VERSION 5.7 ;
BUSBITCHARS "[]" ;
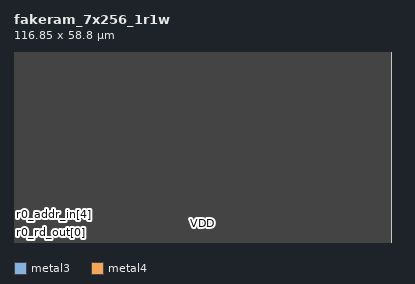
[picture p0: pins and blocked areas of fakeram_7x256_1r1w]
MACRO fakeram_7x256_1r1w
  FOREIGN fakeram_7x256_1r1w 0 0 ;
  SYMMETRY X Y R90 ;
  SIZE 116.850 BY 58.800 ;
  CLASS BLOCK ;
  PIN w0_wd_in[0]
    DIRECTION INPUT ;
    USE SIGNAL ;
    SHAPE ABUTMENT ;
    PORT
      LAYER metal3 ;
      RECT 0.000 0.280 0.140 0.420 ;
    END
  END w0_wd_in[0]
  PIN w0_wd_in[1]
    DIRECTION INPUT ;
    USE SIGNAL ;
    SHAPE ABUTMENT ;
    PORT
      LAYER metal3 ;
      RECT 0.000 0.560 0.140 0.700 ;
    END
  END w0_wd_in[1]
  PIN w0_wd_in[2]
    DIRECTION INPUT ;
    USE SIGNAL ;
    SHAPE ABUTMENT ;
    PORT
      LAYER metal3 ;
      RECT 0.000 0.840 0.140 0.980 ;
    END
  END w0_wd_in[2]
  PIN w0_wd_in[3]
    DIRECTION INPUT ;
    USE SIGNAL ;
    SHAPE ABUTMENT ;
    PORT
      LAYER metal3 ;
      RECT 0.000 1.120 0.140 1.260 ;
    END
  END w0_wd_in[3]
  PIN w0_wd_in[4]
    DIRECTION INPUT ;
    USE SIGNAL ;
    SHAPE ABUTMENT ;
    PORT
      LAYER metal3 ;
      RECT 0.000 1.400 0.140 1.540 ;
    END
  END w0_wd_in[4]
  PIN w0_wd_in[5]
    DIRECTION INPUT ;
    USE SIGNAL ;
    SHAPE ABUTMENT ;
    PORT
      LAYER metal3 ;
      RECT 0.000 1.680 0.140 1.820 ;
    END
  END w0_wd_in[5]
  PIN w0_wd_in[6]
    DIRECTION INPUT ;
    USE SIGNAL ;
    SHAPE ABUTMENT ;
    PORT
      LAYER metal3 ;
      RECT 0.000 1.960 0.140 2.100 ;
    END
  END w0_wd_in[6]
  PIN w0_addr_in[0]
    DIRECTION INPUT ;
    USE SIGNAL ;
    SHAPE ABUTMENT ;
    PORT
      LAYER metal3 ;
      RECT 0.000 2.240 0.140 2.380 ;
    END
  END w0_addr_in[0]
  PIN w0_addr_in[1]
    DIRECTION INPUT ;
    USE SIGNAL ;
    SHAPE ABUTMENT ;
    PORT
      LAYER metal3 ;
      RECT 0.000 2.520 0.140 2.660 ;
    END
  END w0_addr_in[1]
  PIN w0_addr_in[2]
    DIRECTION INPUT ;
    USE SIGNAL ;
    SHAPE ABUTMENT ;
    PORT
      LAYER metal3 ;
      RECT 0.000 2.800 0.140 2.940 ;
    END
  END w0_addr_in[2]
  PIN w0_addr_in[3]
    DIRECTION INPUT ;
    USE SIGNAL ;
    SHAPE ABUTMENT ;
    PORT
      LAYER metal3 ;
      RECT 0.000 3.080 0.140 3.220 ;
    END
  END w0_addr_in[3]
  PIN w0_addr_in[4]
    DIRECTION INPUT ;
    USE SIGNAL ;
    SHAPE ABUTMENT ;
    PORT
      LAYER metal3 ;
      RECT 0.000 3.360 0.140 3.500 ;
    END
  END w0_addr_in[4]
  PIN w0_addr_in[5]
    DIRECTION INPUT ;
    USE SIGNAL ;
    SHAPE ABUTMENT ;
    PORT
      LAYER metal3 ;
      RECT 0.000 3.640 0.140 3.780 ;
    END
  END w0_addr_in[5]
  PIN w0_addr_in[6]
    DIRECTION INPUT ;
    USE SIGNAL ;
    SHAPE ABUTMENT ;
    PORT
      LAYER metal3 ;
      RECT 0.000 3.920 0.140 4.060 ;
    END
  END w0_addr_in[6]
  PIN w0_addr_in[7]
    DIRECTION INPUT ;
    USE SIGNAL ;
    SHAPE ABUTMENT ;
    PORT
      LAYER metal3 ;
      RECT 0.000 4.200 0.140 4.340 ;
    END
  END w0_addr_in[7]
  PIN w0_clk
    DIRECTION INPUT ;
    USE SIGNAL ;
    SHAPE ABUTMENT ;
    PORT
      LAYER metal3 ;
      RECT 0.000 4.480 0.140 4.620 ;
    END
  END w0_clk
  PIN w0_ce_in
    DIRECTION INPUT ;
    USE SIGNAL ;
    SHAPE ABUTMENT ;
    PORT
      LAYER metal3 ;
      RECT 0.000 4.760 0.140 4.900 ;
    END
  END w0_ce_in
  PIN w0_we_in
    DIRECTION INPUT ;
    USE SIGNAL ;
    SHAPE ABUTMENT ;
    PORT
      LAYER metal3 ;
      RECT 0.000 5.040 0.140 5.180 ;
    END
  END w0_we_in
  PIN r0_rd_out[0]
    DIRECTION OUTPUT ;
    USE SIGNAL ;
    SHAPE ABUTMENT ;
    PORT
      LAYER metal3 ;
      RECT 0.000 5.320 0.140 5.460 ;
    END
  END r0_rd_out[0]
  PIN r0_rd_out[1]
    DIRECTION OUTPUT ;
    USE SIGNAL ;
    SHAPE ABUTMENT ;
    PORT
      LAYER metal3 ;
      RECT 0.000 5.600 0.140 5.740 ;
    END
  END r0_rd_out[1]
  PIN r0_rd_out[2]
    DIRECTION OUTPUT ;
    USE SIGNAL ;
    SHAPE ABUTMENT ;
    PORT
      LAYER metal3 ;
      RECT 0.000 5.880 0.140 6.020 ;
    END
  END r0_rd_out[2]
  PIN r0_rd_out[3]
    DIRECTION OUTPUT ;
    USE SIGNAL ;
    SHAPE ABUTMENT ;
    PORT
      LAYER metal3 ;
      RECT 0.000 6.160 0.140 6.300 ;
    END
  END r0_rd_out[3]
  PIN r0_rd_out[4]
    DIRECTION OUTPUT ;
    USE SIGNAL ;
    SHAPE ABUTMENT ;
    PORT
      LAYER metal3 ;
      RECT 0.000 6.440 0.140 6.580 ;
    END
  END r0_rd_out[4]
  PIN r0_rd_out[5]
    DIRECTION OUTPUT ;
    USE SIGNAL ;
    SHAPE ABUTMENT ;
    PORT
      LAYER metal3 ;
      RECT 0.000 6.720 0.140 6.860 ;
    END
  END r0_rd_out[5]
  PIN r0_rd_out[6]
    DIRECTION OUTPUT ;
    USE SIGNAL ;
    SHAPE ABUTMENT ;
    PORT
      LAYER metal3 ;
      RECT 0.000 7.000 0.140 7.140 ;
    END
  END r0_rd_out[6]
  PIN r0_addr_in[0]
    DIRECTION INPUT ;
    USE SIGNAL ;
    SHAPE ABUTMENT ;
    PORT
      LAYER metal3 ;
      RECT 0.000 7.280 0.140 7.420 ;
    END
  END r0_addr_in[0]
  PIN r0_addr_in[1]
    DIRECTION INPUT ;
    USE SIGNAL ;
    SHAPE ABUTMENT ;
    PORT
      LAYER metal3 ;
      RECT 0.000 7.560 0.140 7.700 ;
    END
  END r0_addr_in[1]
  PIN r0_addr_in[2]
    DIRECTION INPUT ;
    USE SIGNAL ;
    SHAPE ABUTMENT ;
    PORT
      LAYER metal3 ;
      RECT 0.000 7.840 0.140 7.980 ;
    END
  END r0_addr_in[2]
  PIN r0_addr_in[3]
    DIRECTION INPUT ;
    USE SIGNAL ;
    SHAPE ABUTMENT ;
    PORT
      LAYER metal3 ;
      RECT 0.000 8.120 0.140 8.260 ;
    END
  END r0_addr_in[3]
  PIN r0_addr_in[4]
    DIRECTION INPUT ;
    USE SIGNAL ;
    SHAPE ABUTMENT ;
    PORT
      LAYER metal3 ;
      RECT 0.000 8.400 0.140 8.540 ;
    END
  END r0_addr_in[4]
  PIN r0_addr_in[5]
    DIRECTION INPUT ;
    USE SIGNAL ;
    SHAPE ABUTMENT ;
    PORT
      LAYER metal3 ;
      RECT 0.000 8.680 0.140 8.820 ;
    END
  END r0_addr_in[5]
  PIN r0_addr_in[6]
    DIRECTION INPUT ;
    USE SIGNAL ;
    SHAPE ABUTMENT ;
    PORT
      LAYER metal3 ;
      RECT 0.000 8.960 0.140 9.100 ;
    END
  END r0_addr_in[6]
  PIN r0_addr_in[7]
    DIRECTION INPUT ;
    USE SIGNAL ;
    SHAPE ABUTMENT ;
    PORT
      LAYER metal3 ;
      RECT 0.000 9.240 0.140 9.380 ;
    END
  END r0_addr_in[7]
  PIN r0_clk
    DIRECTION INPUT ;
    USE SIGNAL ;
    SHAPE ABUTMENT ;
    PORT
      LAYER metal3 ;
      RECT 0.000 9.520 0.140 9.660 ;
    END
  END r0_clk
  PIN r0_ce_in
    DIRECTION INPUT ;
    USE SIGNAL ;
    SHAPE ABUTMENT ;
    PORT
      LAYER metal3 ;
      RECT 0.000 9.800 0.140 9.940 ;
    END
  END r0_ce_in
  PIN VDD
    DIRECTION INOUT ;
    USE POWER ;
    PORT
      LAYER metal4 ;
      RECT 0.190 0.000 116.660 0.140 ;
      RECT 0.190 0.560 116.660 0.700 ;
      RECT 0.190 1.120 116.660 1.260 ;
      RECT 0.190 1.680 116.660 1.820 ;
      RECT 0.190 2.240 116.660 2.380 ;
      RECT 0.190 2.800 116.660 2.940 ;
      RECT 0.190 3.360 116.660 3.500 ;
      RECT 0.190 3.920 116.660 4.060 ;
      RECT 0.190 4.480 116.660 4.620 ;
      RECT 0.190 5.040 116.660 5.180 ;
      RECT 0.190 5.600 116.660 5.740 ;
      RECT 0.190 6.160 116.660 6.300 ;
      RECT 0.190 6.720 116.660 6.860 ;
      RECT 0.190 7.280 116.660 7.420 ;
      RECT 0.190 7.840 116.660 7.980 ;
      RECT 0.190 8.400 116.660 8.540 ;
      RECT 0.190 8.960 116.660 9.100 ;
      RECT 0.190 9.520 116.660 9.660 ;
      RECT 0.190 10.080 116.660 10.220 ;
      RECT 0.190 10.640 116.660 10.780 ;
      RECT 0.190 11.200 116.660 11.340 ;
      RECT 0.190 11.760 116.660 11.900 ;
      RECT 0.190 12.320 116.660 12.460 ;
      RECT 0.190 12.880 116.660 13.020 ;
      RECT 0.190 13.440 116.660 13.580 ;
      RECT 0.190 14.000 116.660 14.140 ;
      RECT 0.190 14.560 116.660 14.700 ;
      RECT 0.190 15.120 116.660 15.260 ;
      RECT 0.190 15.680 116.660 15.820 ;
      RECT 0.190 16.240 116.660 16.380 ;
      RECT 0.190 16.800 116.660 16.940 ;
      RECT 0.190 17.360 116.660 17.500 ;
      RECT 0.190 17.920 116.660 18.060 ;
      RECT 0.190 18.480 116.660 18.620 ;
      RECT 0.190 19.040 116.660 19.180 ;
      RECT 0.190 19.600 116.660 19.740 ;
      RECT 0.190 20.160 116.660 20.300 ;
      RECT 0.190 20.720 116.660 20.860 ;
      RECT 0.190 21.280 116.660 21.420 ;
      RECT 0.190 21.840 116.660 21.980 ;
      RECT 0.190 22.400 116.660 22.540 ;
      RECT 0.190 22.960 116.660 23.100 ;
      RECT 0.190 23.520 116.660 23.660 ;
      RECT 0.190 24.080 116.660 24.220 ;
      RECT 0.190 24.640 116.660 24.780 ;
      RECT 0.190 25.200 116.660 25.340 ;
      RECT 0.190 25.760 116.660 25.900 ;
      RECT 0.190 26.320 116.660 26.460 ;
      RECT 0.190 26.880 116.660 27.020 ;
      RECT 0.190 27.440 116.660 27.580 ;
      RECT 0.190 28.000 116.660 28.140 ;
      RECT 0.190 28.560 116.660 28.700 ;
      RECT 0.190 29.120 116.660 29.260 ;
      RECT 0.190 29.680 116.660 29.820 ;
      RECT 0.190 30.240 116.660 30.380 ;
      RECT 0.190 30.800 116.660 30.940 ;
      RECT 0.190 31.360 116.660 31.500 ;
      RECT 0.190 31.920 116.660 32.060 ;
      RECT 0.190 32.480 116.660 32.620 ;
      RECT 0.190 33.040 116.660 33.180 ;
      RECT 0.190 33.600 116.660 33.740 ;
      RECT 0.190 34.160 116.660 34.300 ;
      RECT 0.190 34.720 116.660 34.860 ;
      RECT 0.190 35.280 116.660 35.420 ;
      RECT 0.190 35.840 116.660 35.980 ;
      RECT 0.190 36.400 116.660 36.540 ;
      RECT 0.190 36.960 116.660 37.100 ;
      RECT 0.190 37.520 116.660 37.660 ;
      RECT 0.190 38.080 116.660 38.220 ;
      RECT 0.190 38.640 116.660 38.780 ;
      RECT 0.190 39.200 116.660 39.340 ;
      RECT 0.190 39.760 116.660 39.900 ;
      RECT 0.190 40.320 116.660 40.460 ;
      RECT 0.190 40.880 116.660 41.020 ;
      RECT 0.190 41.440 116.660 41.580 ;
      RECT 0.190 42.000 116.660 42.140 ;
      RECT 0.190 42.560 116.660 42.700 ;
      RECT 0.190 43.120 116.660 43.260 ;
      RECT 0.190 43.680 116.660 43.820 ;
      RECT 0.190 44.240 116.660 44.380 ;
      RECT 0.190 44.800 116.660 44.940 ;
      RECT 0.190 45.360 116.660 45.500 ;
      RECT 0.190 45.920 116.660 46.060 ;
      RECT 0.190 46.480 116.660 46.620 ;
      RECT 0.190 47.040 116.660 47.180 ;
      RECT 0.190 47.600 116.660 47.740 ;
      RECT 0.190 48.160 116.660 48.300 ;
      RECT 0.190 48.720 116.660 48.860 ;
      RECT 0.190 49.280 116.660 49.420 ;
      RECT 0.190 49.840 116.660 49.980 ;
      RECT 0.190 50.400 116.660 50.540 ;
      RECT 0.190 50.960 116.660 51.100 ;
      RECT 0.190 51.520 116.660 51.660 ;
      RECT 0.190 52.080 116.660 52.220 ;
      RECT 0.190 52.640 116.660 52.780 ;
      RECT 0.190 53.200 116.660 53.340 ;
      RECT 0.190 53.760 116.660 53.900 ;
      RECT 0.190 54.320 116.660 54.460 ;
      RECT 0.190 54.880 116.660 55.020 ;
      RECT 0.190 55.440 116.660 55.580 ;
      RECT 0.190 56.000 116.660 56.140 ;
      RECT 0.190 56.560 116.660 56.700 ;
      RECT 0.190 57.120 116.660 57.260 ;
      RECT 0.190 57.680 116.660 57.820 ;
      RECT 0.190 58.240 116.660 58.380 ;
    END
  END VDD
  PIN VSS
    DIRECTION INOUT ;
    USE GROUND ;
    PORT
      LAYER metal4 ;
      RECT 0.190 0.280 116.660 0.420 ;
      RECT 0.190 0.840 116.660 0.980 ;
      RECT 0.190 1.400 116.660 1.540 ;
      RECT 0.190 1.960 116.660 2.100 ;
      RECT 0.190 2.520 116.660 2.660 ;
      RECT 0.190 3.080 116.660 3.220 ;
      RECT 0.190 3.640 116.660 3.780 ;
      RECT 0.190 4.200 116.660 4.340 ;
      RECT 0.190 4.760 116.660 4.900 ;
      RECT 0.190 5.320 116.660 5.460 ;
      RECT 0.190 5.880 116.660 6.020 ;
      RECT 0.190 6.440 116.660 6.580 ;
      RECT 0.190 7.000 116.660 7.140 ;
      RECT 0.190 7.560 116.660 7.700 ;
      RECT 0.190 8.120 116.660 8.260 ;
      RECT 0.190 8.680 116.660 8.820 ;
      RECT 0.190 9.240 116.660 9.380 ;
      RECT 0.190 9.800 116.660 9.940 ;
      RECT 0.190 10.360 116.660 10.500 ;
      RECT 0.190 10.920 116.660 11.060 ;
      RECT 0.190 11.480 116.660 11.620 ;
      RECT 0.190 12.040 116.660 12.180 ;
      RECT 0.190 12.600 116.660 12.740 ;
      RECT 0.190 13.160 116.660 13.300 ;
      RECT 0.190 13.720 116.660 13.860 ;
      RECT 0.190 14.280 116.660 14.420 ;
      RECT 0.190 14.840 116.660 14.980 ;
      RECT 0.190 15.400 116.660 15.540 ;
      RECT 0.190 15.960 116.660 16.100 ;
      RECT 0.190 16.520 116.660 16.660 ;
      RECT 0.190 17.080 116.660 17.220 ;
      RECT 0.190 17.640 116.660 17.780 ;
      RECT 0.190 18.200 116.660 18.340 ;
      RECT 0.190 18.760 116.660 18.900 ;
      RECT 0.190 19.320 116.660 19.460 ;
      RECT 0.190 19.880 116.660 20.020 ;
      RECT 0.190 20.440 116.660 20.580 ;
      RECT 0.190 21.000 116.660 21.140 ;
      RECT 0.190 21.560 116.660 21.700 ;
      RECT 0.190 22.120 116.660 22.260 ;
      RECT 0.190 22.680 116.660 22.820 ;
      RECT 0.190 23.240 116.660 23.380 ;
      RECT 0.190 23.800 116.660 23.940 ;
      RECT 0.190 24.360 116.660 24.500 ;
      RECT 0.190 24.920 116.660 25.060 ;
      RECT 0.190 25.480 116.660 25.620 ;
      RECT 0.190 26.040 116.660 26.180 ;
      RECT 0.190 26.600 116.660 26.740 ;
      RECT 0.190 27.160 116.660 27.300 ;
      RECT 0.190 27.720 116.660 27.860 ;
      RECT 0.190 28.280 116.660 28.420 ;
      RECT 0.190 28.840 116.660 28.980 ;
      RECT 0.190 29.400 116.660 29.540 ;
      RECT 0.190 29.960 116.660 30.100 ;
      RECT 0.190 30.520 116.660 30.660 ;
      RECT 0.190 31.080 116.660 31.220 ;
      RECT 0.190 31.640 116.660 31.780 ;
      RECT 0.190 32.200 116.660 32.340 ;
      RECT 0.190 32.760 116.660 32.900 ;
      RECT 0.190 33.320 116.660 33.460 ;
      RECT 0.190 33.880 116.660 34.020 ;
      RECT 0.190 34.440 116.660 34.580 ;
      RECT 0.190 35.000 116.660 35.140 ;
      RECT 0.190 35.560 116.660 35.700 ;
      RECT 0.190 36.120 116.660 36.260 ;
      RECT 0.190 36.680 116.660 36.820 ;
      RECT 0.190 37.240 116.660 37.380 ;
      RECT 0.190 37.800 116.660 37.940 ;
      RECT 0.190 38.360 116.660 38.500 ;
      RECT 0.190 38.920 116.660 39.060 ;
      RECT 0.190 39.480 116.660 39.620 ;
      RECT 0.190 40.040 116.660 40.180 ;
      RECT 0.190 40.600 116.660 40.740 ;
      RECT 0.190 41.160 116.660 41.300 ;
      RECT 0.190 41.720 116.660 41.860 ;
      RECT 0.190 42.280 116.660 42.420 ;
      RECT 0.190 42.840 116.660 42.980 ;
      RECT 0.190 43.400 116.660 43.540 ;
      RECT 0.190 43.960 116.660 44.100 ;
      RECT 0.190 44.520 116.660 44.660 ;
      RECT 0.190 45.080 116.660 45.220 ;
      RECT 0.190 45.640 116.660 45.780 ;
      RECT 0.190 46.200 116.660 46.340 ;
      RECT 0.190 46.760 116.660 46.900 ;
      RECT 0.190 47.320 116.660 47.460 ;
      RECT 0.190 47.880 116.660 48.020 ;
      RECT 0.190 48.440 116.660 48.580 ;
      RECT 0.190 49.000 116.660 49.140 ;
      RECT 0.190 49.560 116.660 49.700 ;
      RECT 0.190 50.120 116.660 50.260 ;
      RECT 0.190 50.680 116.660 50.820 ;
      RECT 0.190 51.240 116.660 51.380 ;
      RECT 0.190 51.800 116.660 51.940 ;
      RECT 0.190 52.360 116.660 52.500 ;
      RECT 0.190 52.920 116.660 53.060 ;
      RECT 0.190 53.480 116.660 53.620 ;
      RECT 0.190 54.040 116.660 54.180 ;
      RECT 0.190 54.600 116.660 54.740 ;
      RECT 0.190 55.160 116.660 55.300 ;
      RECT 0.190 55.720 116.660 55.860 ;
      RECT 0.190 56.280 116.660 56.420 ;
      RECT 0.190 56.840 116.660 56.980 ;
      RECT 0.190 57.400 116.660 57.540 ;
      RECT 0.190 57.960 116.660 58.100 ;
      RECT 0.190 58.520 116.660 58.660 ;
    END
  END VSS
  OBS
    LAYER metal1 ;
      RECT 0.000 0.000 116.850 58.800 ;
    LAYER metal2 ;
      RECT 0.000 0.000 116.850 58.800 ;
    LAYER metal3 ;
      RECT 0.000 0.000 116.850 58.800 ;
  END
END fakeram_7x256_1r1w
END LIBRARY
